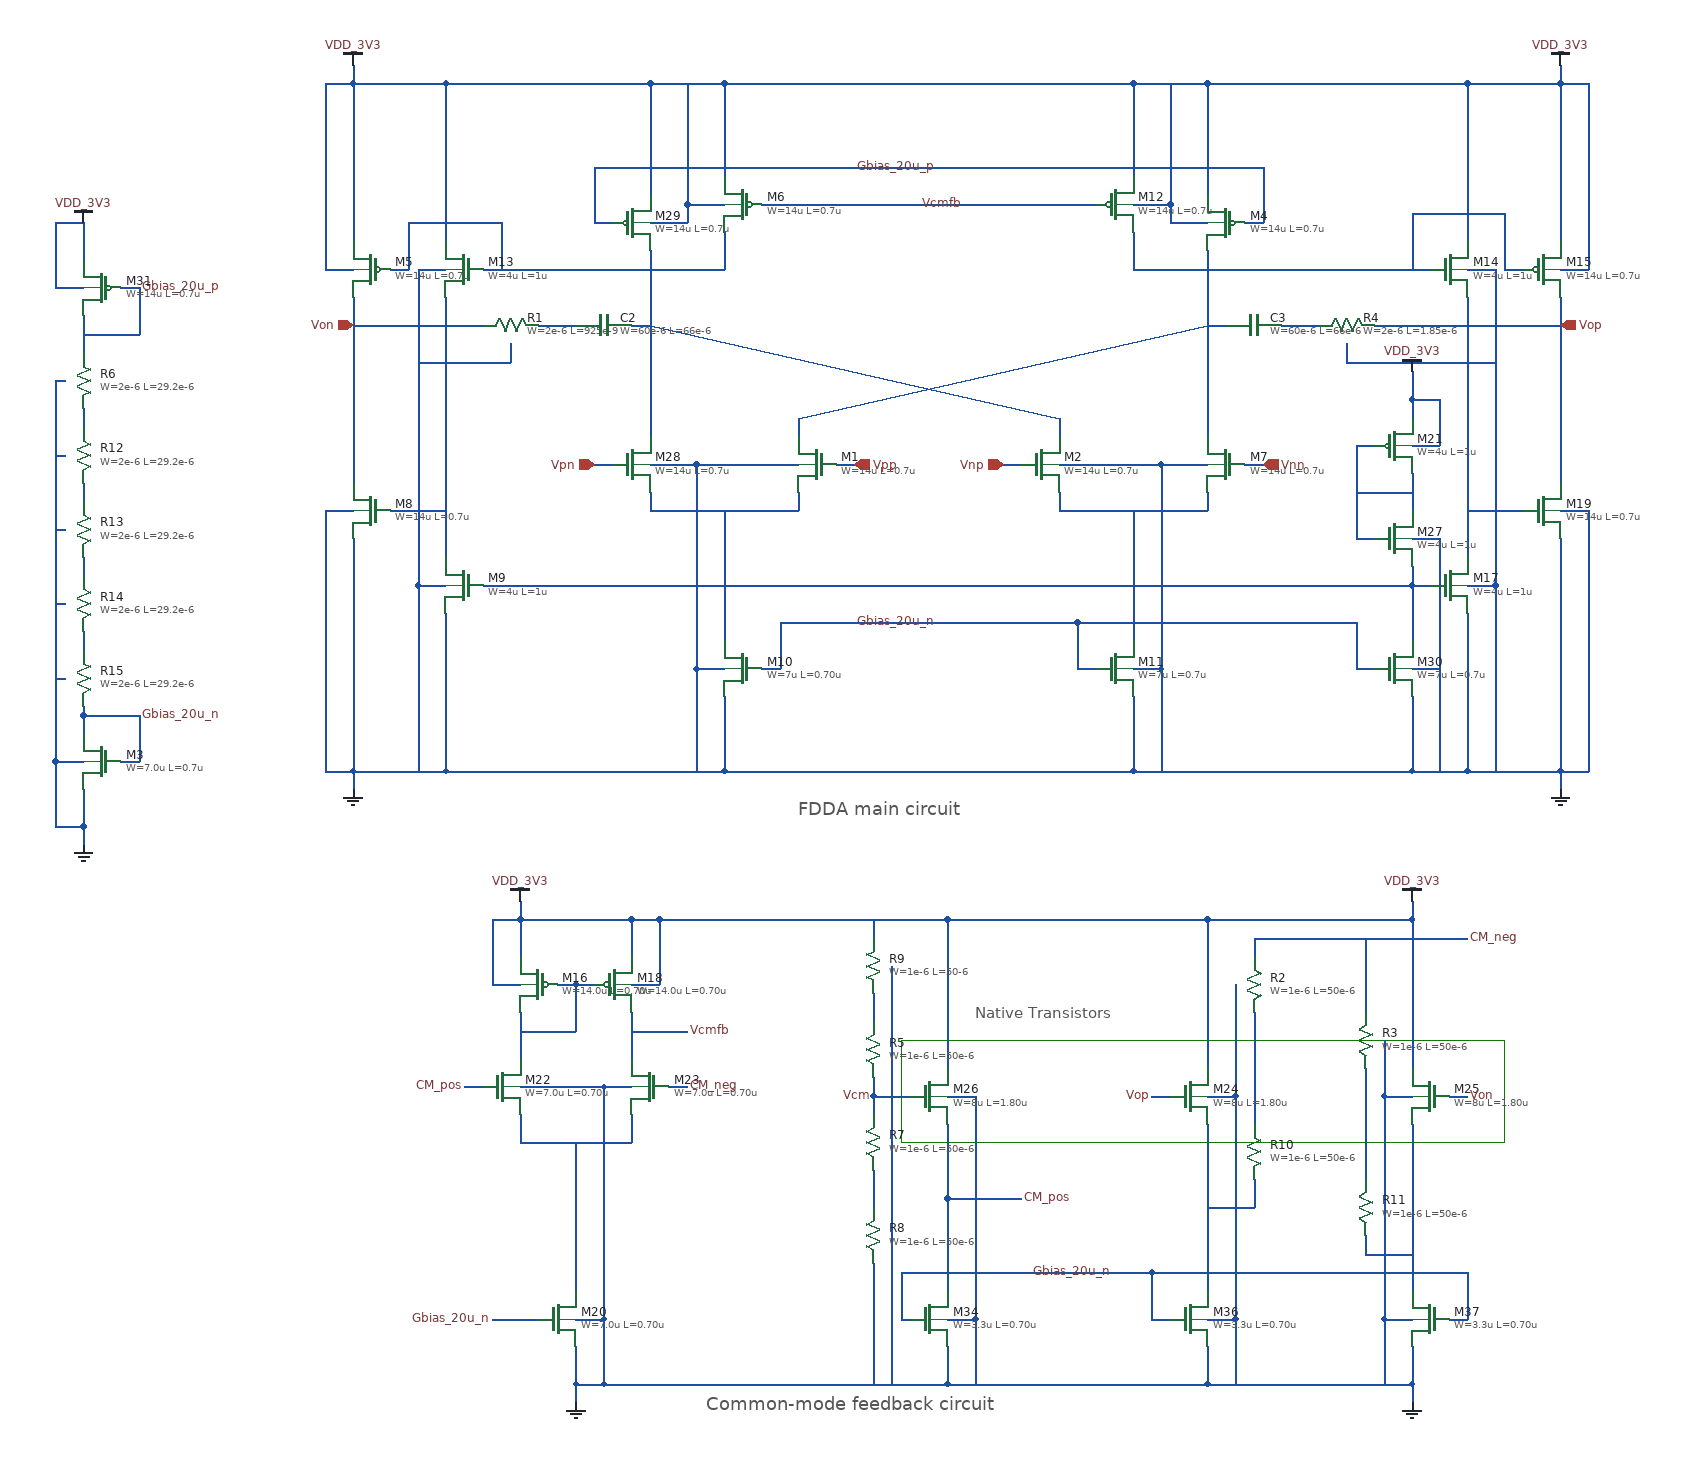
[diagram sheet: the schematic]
v {xschem version=3.4.8RC file_version=1.3}
G {}
K {}
V {}
S {}
F {}
E {}
B 4 1230 -650 1880 -540 {fill=no}
T {Common-mode feedback circuit} 1020 -270 0 0 0.6 0.6 {}
T {FDDA main circuit} 1120 -910 0 0 0.6 0.6 {}
T {Native Transistors} 1310 -690 0 0 0.5 0.5 {}
N 960 -1500 960 -1300 {lab=#net1}
N 1120 -1240 1120 -1220 {lab=#net2}
N 960 -1220 1120 -1220 {lab=#net2}
N 960 -1240 960 -1220 {lab=#net2}
N 1560 -1500 1560 -1300 {lab=#net3}
N 1400 -1240 1400 -1220 {lab=#net4}
N 1400 -1220 1560 -1220 {lab=#net4}
N 1560 -1240 1560 -1220 {lab=#net4}
N 640 -1680 740 -1680 {lab=VDD_3V3}
N 640 -1190 640 -940 {lab=GND}
N 740 -1110 740 -940 {lab=GND}
N 640 -940 740 -940 {lab=GND}
N 900 -1530 920 -1530 {lab=Gbias_20u_p}
N 680 -1220 740 -1220 {lab=#net5}
N 740 -940 900 -940 {lab=GND}
N 900 -940 1040 -940 {lab=GND}
N 1040 -940 1480 -940 {lab=GND}
N 960 -1680 960 -1560 {lab=VDD_3V3}
N 740 -1680 960 -1680 {lab=VDD_3V3}
N 1120 -1320 1120 -1300 {lab=#net3}
N 1400 -1320 1400 -1300 {lab=#net1}
N 640 -1450 640 -1250 {lab=Von}
N 740 -1450 740 -1170 {lab=#net5}
N 640 -1680 640 -1510 {lab=VDD_3V3}
N 740 -1680 740 -1510 {lab=VDD_3V3}
N 780 -1480 960 -1480 {lab=#net1}
N 800 -1530 800 -1480 {lab=#net1}
N 700 -1530 800 -1530 {lab=#net1}
N 700 -1530 700 -1480 {lab=#net1}
N 680 -1480 700 -1480 {lab=#net1}
N 960 -1480 1040 -1480 {lab=#net1}
N 1040 -1520 1040 -1480 {lab=#net1}
N 1040 -1680 1040 -1580 {lab=VDD_3V3}
N 960 -1680 1040 -1680 {lab=VDD_3V3}
N 1480 -1520 1480 -1480 {lab=#net3}
N 1480 -1480 1560 -1480 {lab=#net3}
N 1040 -1680 1480 -1680 {lab=VDD_3V3}
N 1480 -1680 1480 -1580 {lab=VDD_3V3}
N 1480 -1680 1560 -1680 {lab=VDD_3V3}
N 1560 -1680 1560 -1560 {lab=VDD_3V3}
N 1880 -1480 1900 -1480 {lab=#net3}
N 1880 -1540 1880 -1480 {lab=#net3}
N 1780 -1540 1880 -1540 {lab=#net3}
N 1780 -1540 1780 -1480 {lab=#net3}
N 1840 -1680 1840 -1510 {lab=VDD_3V3}
N 1940 -1680 1940 -1510 {lab=VDD_3V3}
N 1840 -1680 1940 -1680 {lab=VDD_3V3}
N 1840 -1450 1840 -1170 {lab=#net6}
N 1840 -1110 1840 -940 {lab=GND}
N 1840 -1220 1900 -1220 {lab=#net6}
N 1940 -1450 1940 -1250 {lab=Vop}
N 1940 -1190 1940 -940 {lab=GND}
N 1840 -940 1940 -940 {lab=GND}
N 1720 -1190 1740 -1190 {lab=#net7}
N 1720 -1290 1720 -1190 {lab=#net7}
N 1720 -1290 1740 -1290 {lab=#net7}
N 1780 -1260 1780 -1220 {lab=#net7}
N 1720 -1240 1780 -1240 {lab=#net7}
N 1780 -1160 1780 -1140 {lab=#net8}
N 1480 -940 1780 -940 {lab=GND}
N 1780 -940 1840 -940 {lab=GND}
N 780 -1140 1780 -1140 {lab=#net8}
N 1780 -1140 1800 -1140 {lab=#net8}
N 1560 -1480 1800 -1480 {lab=#net3}
N 1560 -1680 1840 -1680 {lab=VDD_3V3}
N 1600 -1270 1620 -1270 {lab=Vnn}
N 1340 -1270 1360 -1270 {lab=Vnp}
N 1160 -1270 1180 -1270 {lab=Vpp}
N 900 -1270 920 -1270 {lab=Vpn}
N 880 -710 900 -710 {lab=#net9}
N 1120 -1320 1560 -1420 {lab=#net3}
N 960 -1420 1400 -1320 {lab=#net1}
N 940 -570 940 -540 {lab=#net10}
N 820 -540 940 -540 {lab=#net10}
N 820 -570 820 -540 {lab=#net10}
N 1480 -1020 1480 -940 {lab=GND}
N 390 -950 410 -950 {lab=Gbias_20u_n}
N 1080 -1050 1100 -1050 {lab=Gbias_20u_n}
N 1100 -1100 1100 -1050 {lab=Gbias_20u_n}
N 1100 -1100 1420 -1100 {lab=Gbias_20u_n}
N 1420 -1100 1420 -1050 {lab=Gbias_20u_n}
N 1420 -1050 1440 -1050 {lab=Gbias_20u_n}
N 1040 -1020 1040 -940 {lab=GND}
N 1600 -1530 1620 -1530 {lab=Gbias_20u_p}
N 1000 -1550 1040 -1550 {lab=VDD_3V3}
N 1000 -1550 1000 -1530 {lab=VDD_3V3}
N 960 -1530 1000 -1530 {lab=VDD_3V3}
N 1480 -1550 1520 -1550 {lab=VDD_3V3}
N 1520 -1550 1520 -1530 {lab=VDD_3V3}
N 1520 -1530 1560 -1530 {lab=VDD_3V3}
N 940 -710 970 -710 {lab=VDD_3V3}
N 1940 -1480 1970 -1480 {lab=VDD_3V3}
N 880 -350 910 -350 {lab=GND}
N 1840 -1140 1870 -1140 {lab=GND}
N 1780 -1190 1810 -1190 {lab=GND}
N 1940 -1220 1970 -1220 {lab=GND}
N 1840 -1480 1870 -1480 {lab=GND}
N 320 -950 350 -950 {lab=GND}
N 1010 -1050 1040 -1050 {lab=GND}
N 710 -1140 740 -1140 {lab=GND}
N 610 -1220 640 -1220 {lab=GND}
N 710 -1480 740 -1480 {lab=GND}
N 980 -600 1000 -600 {lab=CM_neg}
N 760 -600 780 -600 {lab=CM_pos}
N 1820 -590 1840 -590 {lab=Von}
N 1500 -590 1520 -590 {lab=Vop}
N 940 -660 1000 -660 {lab=Vcmfb}
N 1560 -320 1560 -280 {lab=GND}
N 1560 -280 1780 -280 {lab=GND}
N 1780 -320 1780 -280 {lab=GND}
N 1750 -350 1780 -350 {lab=GND}
N 1750 -350 1750 -280 {lab=GND}
N 1590 -350 1590 -280 {lab=GND}
N 1560 -350 1590 -350 {lab=GND}
N 1280 -280 1560 -280 {lab=GND}
N 1280 -320 1280 -280 {lab=GND}
N 1080 -280 1280 -280 {lab=GND}
N 1050 -280 1080 -280 {lab=GND}
N 1280 -350 1310 -350 {lab=GND}
N 1310 -350 1310 -280 {lab=GND}
N 1280 -590 1310 -590 {lab=GND}
N 1560 -590 1590 -590 {lab=GND}
N 1750 -590 1780 -590 {lab=GND}
N 1280 -480 1360 -480 {lab=CM_pos}
N 1620 -1590 1620 -1530 {lab=Gbias_20u_p}
N 900 -1590 1620 -1590 {lab=Gbias_20u_p}
N 900 -1590 900 -1530 {lab=Gbias_20u_p}
N 1000 -1680 1000 -1550 {lab=VDD_3V3}
N 1520 -1680 1520 -1550 {lab=VDD_3V3}
N 1870 -1140 1870 -940 {lab=GND}
N 1480 -1050 1510 -1050 {lab=GND}
N 1510 -1050 1510 -940 {lab=GND}
N 1010 -1050 1010 -940 {lab=GND}
N 710 -1140 710 -940 {lab=GND}
N 610 -1220 610 -940 {lab=GND}
N 940 -1420 960 -1420 {lab=#net1}
N 840 -1420 880 -1420 {lab=#net11}
N 1560 -1420 1580 -1420 {lab=#net3}
N 1640 -1420 1680 -1420 {lab=#net12}
N 1970 -1680 1970 -1480 {lab=VDD_3V3}
N 610 -1480 640 -1480 {lab=VDD_3V3}
N 610 -1680 610 -1480 {lab=VDD_3V3}
N 320 -1460 350 -1460 {lab=VDD_3V3}
N 320 -1530 350 -1530 {lab=VDD_3V3}
N 910 -600 910 -350 {lab=GND}
N 910 -600 940 -600 {lab=GND}
N 820 -600 910 -600 {lab=GND}
N 1870 -1480 1870 -1140 {lab=GND}
N 1970 -1220 1970 -940 {lab=GND}
N 1510 -1270 1510 -1050 {lab=GND}
N 1510 -1270 1560 -1270 {lab=GND}
N 1400 -1270 1510 -1270 {lab=GND}
N 1010 -1270 1010 -1050 {lab=GND}
N 960 -1270 1010 -1270 {lab=GND}
N 1010 -1270 1120 -1270 {lab=GND}
N 1780 -1290 1810 -1290 {lab=VDD_3V3}
N 1810 -1340 1810 -1290 {lab=VDD_3V3}
N 1780 -1340 1810 -1340 {lab=VDD_3V3}
N 1810 -1190 1810 -940 {lab=GND}
N 640 -940 640 -920 {lab=GND}
N 1940 -940 1940 -920 {lab=GND}
N 710 -1480 710 -1140 {lab=GND}
N 1940 -940 1970 -940 {lab=GND}
N 1940 -1680 1970 -1680 {lab=VDD_3V3}
N 860 -710 880 -710 {lab=#net9}
N 790 -710 820 -710 {lab=VDD_3V3}
N 880 -710 880 -660 {lab=#net9}
N 820 -680 820 -630 {lab=#net9}
N 940 -680 940 -630 {lab=Vcmfb}
N 910 -350 910 -280 {lab=GND}
N 1820 -350 1840 -350 {lab=Gbias_20u_n}
N 1840 -400 1840 -350 {lab=Gbias_20u_n}
N 1500 -350 1520 -350 {lab=Gbias_20u_n}
N 1500 -400 1500 -350 {lab=Gbias_20u_n}
N 1500 -400 1840 -400 {lab=Gbias_20u_n}
N 910 -280 1050 -280 {lab=GND}
N 820 -780 820 -740 {lab=VDD_3V3}
N 820 -780 940 -780 {lab=VDD_3V3}
N 940 -780 940 -740 {lab=VDD_3V3}
N 940 -780 970 -780 {lab=VDD_3V3}
N 970 -780 970 -710 {lab=VDD_3V3}
N 970 -780 1080 -780 {lab=VDD_3V3}
N 1080 -780 1280 -780 {lab=VDD_3V3}
N 1280 -780 1560 -780 {lab=VDD_3V3}
N 1560 -780 1780 -780 {lab=VDD_3V3}
N 1560 -560 1560 -380 {lab=#net13}
N 1560 -780 1560 -620 {lab=VDD_3V3}
N 1280 -560 1280 -480 {lab=CM_pos}
N 1780 -480 1780 -380 {lab=#net14}
N 1780 -560 1780 -480 {lab=#net14}
N 1780 -780 1780 -620 {lab=VDD_3V3}
N 1750 -590 1750 -350 {lab=GND}
N 1590 -590 1590 -350 {lab=GND}
N 1280 -780 1280 -620 {lab=VDD_3V3}
N 1780 -280 1780 -260 {lab=GND}
N 820 -660 880 -660 {lab=#net9}
N 1080 -1550 1440 -1550 {lab=Vcmfb}
N 1200 -590 1240 -590 {lab=Vcm}
N 1310 -590 1310 -350 {lab=GND}
N 1220 -660 1220 -520 {lab=GND}
N 1780 -1140 1780 -1080 {lab=#net8}
N 1780 -1050 1810 -1050 {lab=GND}
N 1720 -1050 1740 -1050 {lab=Gbias_20u_n}
N 1420 -1100 1720 -1100 {lab=Gbias_20u_n}
N 790 -350 840 -350 {lab=Gbias_20u_n}
N 790 -780 820 -780 {lab=VDD_3V3}
N 790 -780 790 -710 {lab=VDD_3V3}
N 880 -320 880 -280 {lab=GND}
N 880 -280 910 -280 {lab=GND}
N 1720 -1100 1720 -1050 {lab=Gbias_20u_n}
N 880 -280 880 -260 {lab=GND}
N 1390 -400 1500 -400 {lab=Gbias_20u_n}
N 1230 -400 1390 -400 {lab=Gbias_20u_n}
N 1230 -400 1230 -350 {lab=Gbias_20u_n}
N 1780 -800 1780 -780 {lab=VDD_3V3}
N 820 -800 820 -780 {lab=VDD_3V3}
N 1780 -1340 1780 -1320 {lab=VDD_3V3}
N 1780 -1360 1780 -1340 {lab=VDD_3V3}
N 1940 -1700 1940 -1680 {lab=VDD_3V3}
N 640 -1700 640 -1680 {lab=VDD_3V3}
N 410 -1000 410 -950 {lab=Gbias_20u_n}
N 320 -1530 320 -1460 {lab=VDD_3V3}
N 350 -1530 350 -1490 {lab=VDD_3V3}
N 350 -920 350 -880 {lab=GND}
N 320 -880 350 -880 {lab=GND}
N 320 -950 320 -880 {lab=GND}
N 350 -880 350 -860 {lab=GND}
N 610 -940 640 -940 {lab=GND}
N 610 -1680 640 -1680 {lab=VDD_3V3}
N 320 -1360 330 -1360 {lab=GND}
N 390 -1460 410 -1460 {lab=Gbias_20u_p}
N 410 -1460 410 -1410 {lab=Gbias_20u_p}
N 350 -1410 410 -1410 {lab=Gbias_20u_p}
N 350 -1430 350 -1390 {lab=Gbias_20u_p}
N 350 -1000 410 -1000 {lab=Gbias_20u_n}
N 350 -1410 350 -1390 {lab=Gbias_20u_p}
N 880 -540 880 -380 {lab=#net10}
N 1280 -480 1280 -380 {lab=CM_pos}
N 1040 -1220 1040 -1080 {lab=#net2}
N 1480 -1220 1480 -1080 {lab=#net4}
N 1780 -1020 1780 -940 {lab=GND}
N 320 -1360 320 -950 {lab=GND}
N 1220 -520 1220 -460 {lab=GND}
N 810 -1400 810 -1380 {lab=GND}
N 710 -1380 810 -1380 {lab=GND}
N 1710 -1400 1710 -1380 {lab=GND}
N 1710 -1380 1870 -1380 {lab=GND}
N 1780 -1370 1780 -1360 {lab=VDD_3V3}
N 1200 -510 1200 -470 {lab=#net15}
N 1200 -410 1200 -280 {lab=GND}
N 1200 -590 1200 -570 {lab=Vcm}
N 1200 -610 1200 -590 {lab=Vcm}
N 1200 -700 1200 -670 {lab=#net16}
N 1200 -780 1200 -760 {lab=VDD_3V3}
N 1220 -460 1220 -440 {lab=GND}
N 1220 -730 1220 -660 {lab=GND}
N 1230 -350 1240 -350 {lab=Gbias_20u_n}
N 1220 -440 1220 -280 {lab=GND}
N 350 -1000 350 -980 {lab=Gbias_20u_n}
N 350 -1010 350 -1000 {lab=Gbias_20u_n}
N 350 -1090 350 -1070 {lab=#net17}
N 350 -1170 350 -1150 {lab=#net18}
N 350 -1250 350 -1230 {lab=#net19}
N 350 -1330 350 -1310 {lab=#net20}
N 320 -1280 330 -1280 {lab=GND}
N 320 -1200 330 -1200 {lab=GND}
N 320 -1120 330 -1120 {lab=GND}
N 320 -1040 330 -1040 {lab=GND}
N 1740 -1420 1940 -1420 {lab=Vop}
N 640 -1420 780 -1420 {lab=Von}
N 1610 -680 1610 -560 {lab=#net21}
N 1730 -620 1730 -500 {lab=#net22}
N 1610 -500 1610 -470 {lab=#net13}
N 1560 -470 1610 -470 {lab=#net13}
N 1730 -440 1730 -420 {lab=#net14}
N 1730 -420 1780 -420 {lab=#net14}
N 1730 -760 1840 -760 {lab=CM_neg}
N 1610 -760 1610 -740 {lab=CM_neg}
N 1610 -760 1840 -760 {lab=CM_neg}
N 1750 -650 1750 -590 {lab=GND}
N 1590 -710 1590 -590 {lab=GND}
N 1730 -760 1730 -680 {}
C {ipin.sym} 900 -1270 0 0 {name=p1 lab=Vpn}
C {ipin.sym} 1180 -1270 0 1 {name=p2 lab=Vpp}
C {ipin.sym} 1340 -1270 0 0 {name=p3 lab=Vnp}
C {ipin.sym} 1620 -1270 0 1 {name=p4 lab=Vnn}
C {opin.sym} 1940 -1420 0 0 {name=p11 lab=Vop}
C {opin.sym} 640 -1420 0 1 {name=p13 lab=Von}
C {symbols/nfet_03v3.sym} 940 -1270 0 0 {name=M28
L=0.7u
W=14u
nf=1
m=4
ad="'int((nf+1)/2) * W/nf * 0.18u'"
pd="'2*int((nf+1)/2) * (W/nf + 0.18u)'"
as="'int((nf+2)/2) * W/nf * 0.18u'"
ps="'2*int((nf+2)/2) * (W/nf + 0.18u)'"
nrd="'0.18u / W'" nrs="'0.18u / W'"
sa=0 sb=0 sd=0
model=nfet_03v3
spiceprefix=X
}
C {symbols/pfet_03v3.sym} 940 -1530 0 0 {name=M29
L=0.7u
W=14u
nf=1
m=2
ad="'int((nf+1)/2) * W/nf * 0.18u'"
pd="'2*int((nf+1)/2) * (W/nf + 0.18u)'"
as="'int((nf+2)/2) * W/nf * 0.18u'"
ps="'2*int((nf+2)/2) * (W/nf + 0.18u)'"
nrd="'0.18u / W'" nrs="'0.18u / W'"
sa=0 sb=0 sd=0
model=pfet_03v3
spiceprefix=X
}
C {gnd.sym} 640 -920 0 0 {name=l1 lab=GND}
C {symbols/pfet_03v3.sym} 370 -1460 0 1 {name=M31
L=0.7u
W=14u
nf=1
m=1
ad="'int((nf+1)/2) * W/nf * 0.18u'"
pd="'2*int((nf+1)/2) * (W/nf + 0.18u)'"
as="'int((nf+2)/2) * W/nf * 0.18u'"
ps="'2*int((nf+2)/2) * (W/nf + 0.18u)'"
nrd="'0.18u / W'" nrs="'0.18u / W'"
sa=0 sb=0 sd=0
model=pfet_03v3
spiceprefix=X
}
C {symbols/pfet_03v3.sym} 660 -1480 0 1 {name=M5
L=0.7u
W=14u
nf=1
m=8
ad="'int((nf+1)/2) * W/nf * 0.18u'"
pd="'2*int((nf+1)/2) * (W/nf + 0.18u)'"
as="'int((nf+2)/2) * W/nf * 0.18u'"
ps="'2*int((nf+2)/2) * (W/nf + 0.18u)'"
nrd="'0.18u / W'" nrs="'0.18u / W'"
sa=0 sb=0 sd=0
model=pfet_03v3
spiceprefix=X
}
C {symbols/pfet_03v3.sym} 1060 -1550 0 1 {name=M6
L=0.7u
W=14u
nf=1
m=2
ad="'int((nf+1)/2) * W/nf * 0.18u'"
pd="'2*int((nf+1)/2) * (W/nf + 0.18u)'"
as="'int((nf+2)/2) * W/nf * 0.18u'"
ps="'2*int((nf+2)/2) * (W/nf + 0.18u)'"
nrd="'0.18u / W'" nrs="'0.18u / W'"
sa=0 sb=0 sd=0
model=pfet_03v3
spiceprefix=X
}
C {symbols/pfet_03v3.sym} 1580 -1530 0 1 {name=M4
L=0.7u
W=14u
nf=1
m=2
ad="'int((nf+1)/2) * W/nf * 0.18u'"
pd="'2*int((nf+1)/2) * (W/nf + 0.18u)'"
as="'int((nf+2)/2) * W/nf * 0.18u'"
ps="'2*int((nf+2)/2) * (W/nf + 0.18u)'"
nrd="'0.18u / W'" nrs="'0.18u / W'"
sa=0 sb=0 sd=0
model=pfet_03v3
spiceprefix=X
}
C {symbols/pfet_03v3.sym} 1460 -1550 0 0 {name=M12
L=0.7u
W=14u
nf=1
m=2
ad="'int((nf+1)/2) * W/nf * 0.18u'"
pd="'2*int((nf+1)/2) * (W/nf + 0.18u)'"
as="'int((nf+2)/2) * W/nf * 0.18u'"
ps="'2*int((nf+2)/2) * (W/nf + 0.18u)'"
nrd="'0.18u / W'" nrs="'0.18u / W'"
sa=0 sb=0 sd=0
model=pfet_03v3
spiceprefix=X
}
C {symbols/pfet_03v3.sym} 1920 -1480 0 0 {name=M15
L=0.7u
W=14u
nf=1
m=8
ad="'int((nf+1)/2) * W/nf * 0.18u'"
pd="'2*int((nf+1)/2) * (W/nf + 0.18u)'"
as="'int((nf+2)/2) * W/nf * 0.18u'"
ps="'2*int((nf+2)/2) * (W/nf + 0.18u)'"
nrd="'0.18u / W'" nrs="'0.18u / W'"
sa=0 sb=0 sd=0
model=pfet_03v3
spiceprefix=X
}
C {symbols/pfet_03v3.sym} 840 -710 0 1 {name=M16
L=0.70u
W=14.0u
nf=1
m=1
ad="'int((nf+1)/2) * W/nf * 0.18u'"
pd="'2*int((nf+1)/2) * (W/nf + 0.18u)'"
as="'int((nf+2)/2) * W/nf * 0.18u'"
ps="'2*int((nf+2)/2) * (W/nf + 0.18u)'"
nrd="'0.18u / W'" nrs="'0.18u / W'"
sa=0 sb=0 sd=0
model=pfet_03v3
spiceprefix=X
}
C {symbols/pfet_03v3.sym} 920 -710 0 0 {name=M18
L=0.70u
W=14.0u
nf=1
m=1
ad="'int((nf+1)/2) * W/nf * 0.18u'"
pd="'2*int((nf+1)/2) * (W/nf + 0.18u)'"
as="'int((nf+2)/2) * W/nf * 0.18u'"
ps="'2*int((nf+2)/2) * (W/nf + 0.18u)'"
nrd="'0.18u / W'" nrs="'0.18u / W'"
sa=0 sb=0 sd=0
model=pfet_03v3
spiceprefix=X
}
C {symbols/nfet_03v3.sym} 1140 -1270 0 1 {name=M1
L=0.7u
W=14u
nf=1
m=4
ad="'int((nf+1)/2) * W/nf * 0.18u'"
pd="'2*int((nf+1)/2) * (W/nf + 0.18u)'"
as="'int((nf+2)/2) * W/nf * 0.18u'"
ps="'2*int((nf+2)/2) * (W/nf + 0.18u)'"
nrd="'0.18u / W'" nrs="'0.18u / W'"
sa=0 sb=0 sd=0
model=nfet_03v3
spiceprefix=X
}
C {symbols/nfet_03v3.sym} 1380 -1270 0 0 {name=M2
L=0.7u
W=14u
nf=1
m=4
ad="'int((nf+1)/2) * W/nf * 0.18u'"
pd="'2*int((nf+1)/2) * (W/nf + 0.18u)'"
as="'int((nf+2)/2) * W/nf * 0.18u'"
ps="'2*int((nf+2)/2) * (W/nf + 0.18u)'"
nrd="'0.18u / W'" nrs="'0.18u / W'"
sa=0 sb=0 sd=0
model=nfet_03v3
spiceprefix=X
}
C {symbols/nfet_03v3.sym} 1580 -1270 0 1 {name=M7
L=0.7u
W=14u
nf=1
m=4
ad="'int((nf+1)/2) * W/nf * 0.18u'"
pd="'2*int((nf+1)/2) * (W/nf + 0.18u)'"
as="'int((nf+2)/2) * W/nf * 0.18u'"
ps="'2*int((nf+2)/2) * (W/nf + 0.18u)'"
nrd="'0.18u / W'" nrs="'0.18u / W'"
sa=0 sb=0 sd=0
model=nfet_03v3
spiceprefix=X
}
C {symbols/nfet_03v3.sym} 370 -950 0 1 {name=M3
L=0.7u
W=7.0u
nf=1
m=1
ad="'int((nf+1)/2) * W/nf * 0.18u'"
pd="'2*int((nf+1)/2) * (W/nf + 0.18u)'"
as="'int((nf+2)/2) * W/nf * 0.18u'"
ps="'2*int((nf+2)/2) * (W/nf + 0.18u)'"
nrd="'0.18u / W'" nrs="'0.18u / W'"
sa=0 sb=0 sd=0
model=nfet_03v3
spiceprefix=X
}
C {symbols/nfet_03v3.sym} 1060 -1050 0 1 {name=M10
L=0.70u
W=7u
nf=1
m=4
ad="'int((nf+1)/2) * W/nf * 0.18u'"
pd="'2*int((nf+1)/2) * (W/nf + 0.18u)'"
as="'int((nf+2)/2) * W/nf * 0.18u'"
ps="'2*int((nf+2)/2) * (W/nf + 0.18u)'"
nrd="'0.18u / W'" nrs="'0.18u / W'"
sa=0 sb=0 sd=0
model=nfet_03v3
spiceprefix=X
}
C {symbols/nfet_03v3.sym} 1460 -1050 0 0 {name=M11
L=0.7u
W=7u
nf=1
m=4
ad="'int((nf+1)/2) * W/nf * 0.18u'"
pd="'2*int((nf+1)/2) * (W/nf + 0.18u)'"
as="'int((nf+2)/2) * W/nf * 0.18u'"
ps="'2*int((nf+2)/2) * (W/nf + 0.18u)'"
nrd="'0.18u / W'" nrs="'0.18u / W'"
sa=0 sb=0 sd=0
model=nfet_03v3
spiceprefix=X
}
C {symbols/nfet_03v3.sym} 1920 -1220 0 0 {name=M19
L=0.7u
W=14u
nf=1
m=4
ad="'int((nf+1)/2) * W/nf * 0.18u'"
pd="'2*int((nf+1)/2) * (W/nf + 0.18u)'"
as="'int((nf+2)/2) * W/nf * 0.18u'"
ps="'2*int((nf+2)/2) * (W/nf + 0.18u)'"
nrd="'0.18u / W'" nrs="'0.18u / W'"
sa=0 sb=0 sd=0
model=nfet_03v3
spiceprefix=X
}
C {symbols/nfet_03v3.sym} 860 -350 0 0 {name=M20
L=0.70u
W=7.0u
nf=1
m=1
ad="'int((nf+1)/2) * W/nf * 0.18u'"
pd="'2*int((nf+1)/2) * (W/nf + 0.18u)'"
as="'int((nf+2)/2) * W/nf * 0.18u'"
ps="'2*int((nf+2)/2) * (W/nf + 0.18u)'"
nrd="'0.18u / W'" nrs="'0.18u / W'"
sa=0 sb=0 sd=0
model=nfet_03v3
spiceprefix=X
}
C {symbols/nfet_03v3.sym} 800 -600 0 0 {name=M22
L=0.70u
W=7.0u
nf=1
m=2
ad="'int((nf+1)/2) * W/nf * 0.18u'"
pd="'2*int((nf+1)/2) * (W/nf + 0.18u)'"
as="'int((nf+2)/2) * W/nf * 0.18u'"
ps="'2*int((nf+2)/2) * (W/nf + 0.18u)'"
nrd="'0.18u / W'" nrs="'0.18u / W'"
sa=0 sb=0 sd=0
model=nfet_03v3
spiceprefix=X
}
C {symbols/nfet_03v3.sym} 660 -1220 0 1 {name=M8
L=0.7u
W=14u
nf=1
m=4
ad="'int((nf+1)/2) * W/nf * 0.18u'"
pd="'2*int((nf+1)/2) * (W/nf + 0.18u)'"
as="'int((nf+2)/2) * W/nf * 0.18u'"
ps="'2*int((nf+2)/2) * (W/nf + 0.18u)'"
nrd="'0.18u / W'" nrs="'0.18u / W'"
sa=0 sb=0 sd=0
model=nfet_03v3
spiceprefix=X
}
C {symbols/nfet_03v3.sym} 960 -600 0 1 {name=M23
L=0.70u
W=7.0u
nf=1
m=2
ad="'int((nf+1)/2) * W/nf * 0.18u'"
pd="'2*int((nf+1)/2) * (W/nf + 0.18u)'"
as="'int((nf+2)/2) * W/nf * 0.18u'"
ps="'2*int((nf+2)/2) * (W/nf + 0.18u)'"
nrd="'0.18u / W'" nrs="'0.18u / W'"
sa=0 sb=0 sd=0
model=nfet_03v3
spiceprefix=X
}
C {gnd.sym} 1940 -920 0 0 {name=l11 lab=GND}
C {lab_wire.sym} 1000 -660 0 1 {name=p15 sig_type=std_logic lab=Vcmfb}
C {lab_wire.sym} 1000 -600 0 1 {name=p5 sig_type=std_logic lab=CM_neg}
C {lab_wire.sym} 760 -600 0 0 {name=p6 sig_type=std_logic lab=CM_pos}
C {lab_wire.sym} 1840 -760 0 1 {name=p9 sig_type=std_logic lab=CM_neg}
C {lab_wire.sym} 1360 -480 0 1 {name=p19 sig_type=std_logic lab=CM_pos}
C {title-3.sym} 0 0 0 0 {name=F1
title="FDDA with Native MOS CMFB"
author="UFJF On Chip"
rev=1.0
page="1"
pages="1"
lock=true
"
}
C {lab_wire.sym} 1200 -590 0 0 {name=p8 sig_type=std_logic lab=Vcm}
C {vdd.sym} 820 -800 0 0 {name=l6 lab=VDD_3V3}
C {vdd.sym} 1780 -800 0 0 {name=l7 lab=VDD_3V3}
C {gnd.sym} 1780 -260 0 0 {name=l9 lab=GND}
C {lab_wire.sym} 1250 -1550 0 1 {name=p7 sig_type=std_logic lab=Vcmfb}
C {symbols/nfet_06v0_nvt.sym} 1540 -590 0 0 {name=M24
L=1.80u
W=8u
nf=1
m=1
ad="'int((nf+1)/2) * W/nf * 0.18u'"
pd="'2*int((nf+1)/2) * (W/nf + 0.18u)'"
as="'int((nf+2)/2) * W/nf * 0.18u'"
ps="'2*int((nf+2)/2) * (W/nf + 0.18u)'"
nrd="'0.18u / W'" nrs="'0.18u / W'"
sa=0 sb=0 sd=0
model=nfet_06v0_nvt
spiceprefix=X
}
C {symbols/nfet_06v0_nvt.sym} 1800 -590 0 1 {name=M25
L=1.80u
W=8u
nf=1
m=1
ad="'int((nf+1)/2) * W/nf * 0.18u'"
pd="'2*int((nf+1)/2) * (W/nf + 0.18u)'"
as="'int((nf+2)/2) * W/nf * 0.18u'"
ps="'2*int((nf+2)/2) * (W/nf + 0.18u)'"
nrd="'0.18u / W'" nrs="'0.18u / W'"
sa=0 sb=0 sd=0
model=nfet_06v0_nvt
spiceprefix=X
}
C {symbols/nfet_06v0_nvt.sym} 1260 -590 0 0 {name=M26
L=1.80u
W=8u
nf=1
m=1
ad="'int((nf+1)/2) * W/nf * 0.18u'"
pd="'2*int((nf+1)/2) * (W/nf + 0.18u)'"
as="'int((nf+2)/2) * W/nf * 0.18u'"
ps="'2*int((nf+2)/2) * (W/nf + 0.18u)'"
nrd="'0.18u / W'" nrs="'0.18u / W'"
sa=0 sb=0 sd=0
model=nfet_06v0_nvt
spiceprefix=X
}
C {symbols/ppolyf_u_1k.sym} 1710 -1420 3 0 {name=R4
W=2e-6
L=1.85e-6
model=ppolyf_u_1k
spiceprefix=X
m=1
}
C {symbols/ppolyf_u_1k.sym} 810 -1420 3 0 {name=R1
W=2e-6
L=925e-9
model=ppolyf_u_1k
spiceprefix=X
m=1
}
C {symbols/ppolyf_u_1k.sym} 1610 -710 0 0 {name=R2
W=1e-6
L=50e-6
model=ppolyf_u_1k
spiceprefix=X
m=1
}
C {symbols/ppolyf_u_1k.sym} 1730 -650 0 1 {name=R3
W=1e-6
L=50e-6
model=ppolyf_u_1k
spiceprefix=X
m=1}
C {symbols/ppolyf_u_1k.sym} 1200 -640 2 0 {name=R5
W=1e-6
L=50e-6
model=ppolyf_u_1k
spiceprefix=X
m=1
}
C {symbols/ppolyf_u_1k.sym} 1200 -540 2 0 {name=R7
W=1e-6
L=50e-6
model=ppolyf_u_1k
spiceprefix=X
m=1
}
C {symbols/cap_mim_2f0fF.sym} 1610 -1420 1 0 {name=C3
W=60e-6
L=66e-6
model=cap_mim_2f0fF
spiceprefix=X
m=2}
C {symbols/cap_mim_2f0fF.sym} 910 -1420 1 0 {name=C2
W=60e-6
L=66e-6
model=cap_mim_2f0fF
spiceprefix=X
m=2}
C {symbols/nfet_03v3.sym} 1820 -1480 0 0 {name=M14
L=1u
W=4u
nf=1
m=1
ad="'int((nf+1)/2) * W/nf * 0.18u'"
pd="'2*int((nf+1)/2) * (W/nf + 0.18u)'"
as="'int((nf+2)/2) * W/nf * 0.18u'"
ps="'2*int((nf+2)/2) * (W/nf + 0.18u)'"
nrd="'0.18u / W'" nrs="'0.18u / W'"
sa=0 sb=0 sd=0
model=nfet_03v3
spiceprefix=X
}
C {symbols/nfet_03v3.sym} 1820 -1140 0 0 {name=M17
L=1u
W=4u
nf=1
m=1
ad="'int((nf+1)/2) * W/nf * 0.18u'"
pd="'2*int((nf+1)/2) * (W/nf + 0.18u)'"
as="'int((nf+2)/2) * W/nf * 0.18u'"
ps="'2*int((nf+2)/2) * (W/nf + 0.18u)'"
nrd="'0.18u / W'" nrs="'0.18u / W'"
sa=0 sb=0 sd=0
model=nfet_03v3
spiceprefix=X
}
C {symbols/nfet_03v3.sym} 1760 -1190 0 0 {name=M27
L=1u
W=4u
nf=1
m=1
ad="'int((nf+1)/2) * W/nf * 0.18u'"
pd="'2*int((nf+1)/2) * (W/nf + 0.18u)'"
as="'int((nf+2)/2) * W/nf * 0.18u'"
ps="'2*int((nf+2)/2) * (W/nf + 0.18u)'"
nrd="'0.18u / W'" nrs="'0.18u / W'"
sa=0 sb=0 sd=0
model=nfet_03v3
spiceprefix=X
}
C {symbols/pfet_03v3.sym} 1760 -1290 0 0 {name=M21
L=1u
W=4u
nf=1
m=1
ad="'int((nf+1)/2) * W/nf * 0.18u'"
pd="'2*int((nf+1)/2) * (W/nf + 0.18u)'"
as="'int((nf+2)/2) * W/nf * 0.18u'"
ps="'2*int((nf+2)/2) * (W/nf + 0.18u)'"
nrd="'0.18u / W'" nrs="'0.18u / W'"
sa=0 sb=0 sd=0
model=pfet_03v3
spiceprefix=X
}
C {symbols/nfet_03v3.sym} 760 -1140 2 0 {name=M9
L=1u
W=4u
nf=1
m=1
ad="'int((nf+1)/2) * W/nf * 0.18u'"
pd="'2*int((nf+1)/2) * (W/nf + 0.18u)'"
as="'int((nf+2)/2) * W/nf * 0.18u'"
ps="'2*int((nf+2)/2) * (W/nf + 0.18u)'"
nrd="'0.18u / W'" nrs="'0.18u / W'"
sa=0 sb=0 sd=0
model=nfet_03v3
spiceprefix=X
}
C {symbols/nfet_03v3.sym} 760 -1480 2 0 {name=M13
L=1u
W=4u
nf=1
m=1
ad="'int((nf+1)/2) * W/nf * 0.18u'"
pd="'2*int((nf+1)/2) * (W/nf + 0.18u)'"
as="'int((nf+2)/2) * W/nf * 0.18u'"
ps="'2*int((nf+2)/2) * (W/nf + 0.18u)'"
nrd="'0.18u / W'" nrs="'0.18u / W'"
sa=0 sb=0 sd=0
model=nfet_03v3
spiceprefix=X
}
C {symbols/nfet_03v3.sym} 1760 -1050 0 0 {name=M30
L=0.7u
W=7u
nf=1
m=1
ad="'int((nf+1)/2) * W/nf * 0.18u'"
pd="'2*int((nf+1)/2) * (W/nf + 0.18u)'"
as="'int((nf+2)/2) * W/nf * 0.18u'"
ps="'2*int((nf+2)/2) * (W/nf + 0.18u)'"
nrd="'0.18u / W'" nrs="'0.18u / W'"
sa=0 sb=0 sd=0
model=nfet_03v3
spiceprefix=X
}
C {gnd.sym} 880 -260 0 0 {name=l5 lab=GND}
C {symbols/nfet_03v3.sym} 1260 -350 0 0 {name=M34
L=0.70u
W=3.3u
nf=1
m=1
ad="'int((nf+1)/2) * W/nf * 0.18u'"
pd="'2*int((nf+1)/2) * (W/nf + 0.18u)'"
as="'int((nf+2)/2) * W/nf * 0.18u'"
ps="'2*int((nf+2)/2) * (W/nf + 0.18u)'"
nrd="'0.18u / W'" nrs="'0.18u / W'"
sa=0 sb=0 sd=0
model=nfet_03v3
spiceprefix=X
}
C {symbols/nfet_03v3.sym} 1540 -350 0 0 {name=M36
L=0.70u
W=3.3u
nf=1
m=1
ad="'int((nf+1)/2) * W/nf * 0.18u'"
pd="'2*int((nf+1)/2) * (W/nf + 0.18u)'"
as="'int((nf+2)/2) * W/nf * 0.18u'"
ps="'2*int((nf+2)/2) * (W/nf + 0.18u)'"
nrd="'0.18u / W'" nrs="'0.18u / W'"
sa=0 sb=0 sd=0
model=nfet_03v3
spiceprefix=X
}
C {symbols/nfet_03v3.sym} 1800 -350 0 1 {name=M37
L=0.70u
W=3.3u
nf=1
m=1
ad="'int((nf+1)/2) * W/nf * 0.18u'"
pd="'2*int((nf+1)/2) * (W/nf + 0.18u)'"
as="'int((nf+2)/2) * W/nf * 0.18u'"
ps="'2*int((nf+2)/2) * (W/nf + 0.18u)'"
nrd="'0.18u / W'" nrs="'0.18u / W'"
sa=0 sb=0 sd=0
model=nfet_03v3
spiceprefix=X
}
C {vdd.sym} 1940 -1700 0 0 {name=l8 lab=VDD_3V3}
C {vdd.sym} 640 -1700 0 0 {name=l2 lab=VDD_3V3}
C {vdd.sym} 1780 -1370 0 0 {name=l4 lab=VDD_3V3}
C {vdd.sym} 350 -1530 0 0 {name=l3 lab=VDD_3V3}
C {lab_wire.sym} 1500 -590 0 0 {name=p12 sig_type=std_logic lab=Vop}
C {lab_wire.sym} 1840 -590 0 1 {name=p14 sig_type=std_logic lab=Von}
C {gnd.sym} 350 -860 0 0 {name=l10 lab=GND}
C {lab_wire.sym} 410 -1000 0 1 {name=p17 sig_type=std_logic lab=Gbias_20u_n}
C {lab_wire.sym} 410 -1460 0 1 {name=p18 sig_type=std_logic lab=Gbias_20u_p}
C {lab_wire.sym} 1180 -1590 0 1 {name=p20 sig_type=std_logic lab=Gbias_20u_p}
C {lab_wire.sym} 1180 -1100 0 1 {name=p21 sig_type=std_logic lab=Gbias_20u_n}
C {lab_wire.sym} 1370 -400 0 1 {name=p10 sig_type=std_logic lab=Gbias_20u_n}
C {lab_wire.sym} 790 -350 0 0 {name=p22 sig_type=std_logic lab=Gbias_20u_n}
C {symbols/ppolyf_u_1k.sym} 350 -1360 0 0 {name=R6
W=2e-6
L=29.2e-6
model=ppolyf_u_1k
spiceprefix=X
m=1
}
C {symbols/ppolyf_u_1k.sym} 1200 -440 2 0 {name=R8
W=1e-6
L=50e-6
model=ppolyf_u_1k
spiceprefix=X
m=1
}
C {symbols/ppolyf_u_1k.sym} 1200 -730 2 0 {name=R9
W=1e-6
L=50-6
model=ppolyf_u_1k
spiceprefix=X
m=1
}
C {symbols/ppolyf_u_1k.sym} 350 -1280 0 0 {name=R12
W=2e-6
L=29.2e-6
model=ppolyf_u_1k
spiceprefix=X
m=1
}
C {symbols/ppolyf_u_1k.sym} 350 -1200 0 0 {name=R13
W=2e-6
L=29.2e-6
model=ppolyf_u_1k
spiceprefix=X
m=1
}
C {symbols/ppolyf_u_1k.sym} 350 -1120 0 0 {name=R14
W=2e-6
L=29.2e-6
model=ppolyf_u_1k
spiceprefix=X
m=1
}
C {symbols/ppolyf_u_1k.sym} 350 -1040 0 0 {name=R15
W=2e-6
L=29.2e-6
model=ppolyf_u_1k
spiceprefix=X
m=1
}
C {symbols/ppolyf_u_1k.sym} 1610 -530 0 0 {name=R10
W=1e-6
L=50e-6
model=ppolyf_u_1k
spiceprefix=X
m=1}
C {symbols/ppolyf_u_1k.sym} 1730 -470 0 1 {name=R11
W=1e-6
L=50e-6
model=ppolyf_u_1k
spiceprefix=X
m=1}
